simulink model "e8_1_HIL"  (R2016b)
settings: Solver=FixedStepDiscrete  StartTime=0.0  StopTime=10.0  RelTol=1e-3
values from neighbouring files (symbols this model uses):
  DEG2RAD = 0.0174533    [Init_control.m]
  Kd_PITCH_AgngleRate = 0.001    [Init_control.m]
  Kd_ROLL_AgngleRate = 0.001    [Init_control.m]
  Kd_YAW_AngleRate = 0.00    (= 0)    [Init_control.m]
  Ki_PITCH_AgngleRate = 0.02    [Init_control.m]
  Ki_ROLL_AgngleRate = 0.02    [Init_control.m]
  Ki_YAW_AngleRate = 0.01    [Init_control.m]
  Kp_PITCH_AgngleRate = 0.1    [Init_control.m]
  Kp_PITCH_ANGLE = 6.5    [Init_control.m]
  Kp_ROLL_AgngleRate = 0.1    [Init_control.m]
  Kp_ROLL_ANGLE = 6.5    [Init_control.m]
  Kp_YAW_AngleRate = 0.5    [Init_control.m]
  Kpxp = 1.0    (= 1)    [Init_control.m]
  Kpyp = 1.0    (= 1)    [Init_control.m]
  Kpzp = 4.0    (= 4)    [Init_control.m]
  Kvxd = 0.01    [Init_control.m]
  Kvxi = 0.1    [Init_control.m]
  Kvxp = 3.0    (= 3)    [Init_control.m]
  Kvyd = 0.01    [Init_control.m]
  Kvyi = 0.1    [Init_control.m]
  Kvyp = 3.0    (= 3)    [Init_control.m]
  Kvzd = 0.005    [Init_control.m]
  Kvzi = 0.01    [Init_control.m]
  Kvzp = 0.45    [Init_control.m]
  MAX_CONTROL_ANGLE_PITCH = 35    [Init_control.m]
  MAX_CONTROL_ANGLE_RATE_PITCH = 220    [Init_control.m]
  MAX_CONTROL_ANGLE_RATE_ROLL = 220    [Init_control.m]
  MAX_CONTROL_ANGLE_RATE_Y = 200    [Init_control.m]
  MAX_CONTROL_ANGLE_ROLL = 35    [Init_control.m]
  MAX_CONTROL_VELOCITY_XY = 5    [Init_control.m]
  MAX_CONTROL_VELOCITY_Z = 3    [Init_control.m]
  Saturation_I_ah = 3.43    [Init_control.m]
  Saturation_I_az = 5    [Init_control.m]
  Saturation_I_RP_Max = 0.3    [Init_control.m]
  Saturation_I_RP_Min = -0.3    [Init_control.m]
  Saturation_I_Y_Max = 0.2    [Init_control.m]
  Saturation_I_Y_Min = -0.2    [Init_control.m]
  THR_HOVER = 0.609    [Init_control.m]
undefined symbols (not defined in the file or in its folder): DiscIntNeverNeededParam, KiRollAttitude, RGBLED_COLOR_ENUM, RGBLED_MODE_ENUM
libraries: simulink x10, pixhawk_slib_sensors_actuators x4, pixhawk_slib_uORB_RW x2

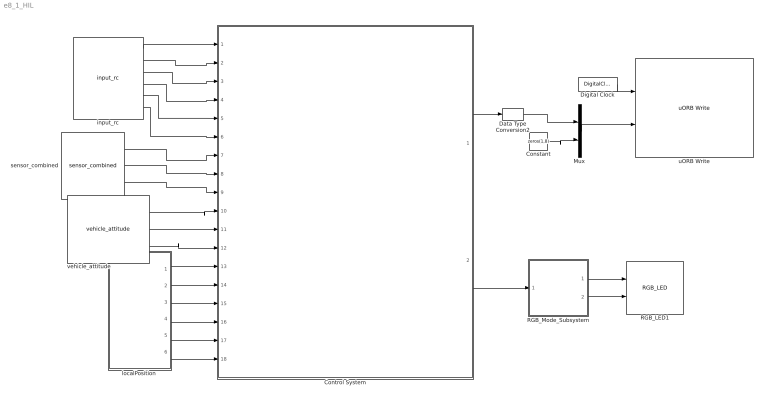
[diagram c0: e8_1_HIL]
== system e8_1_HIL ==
  Constant : Constant  Value=zeros(1,8)
  Control System : Subsystem
  Data Type Conversion2 : DataTypeConversion  OutDataTypeStr=double
  Digital Clock : DigitalClock  SampleTime=-1
  Mux : Mux  Inputs=2
  RGB_LED1 : pixhawk_slib_sensors_actuators/RGB_LED
  RGB_Mode_Subsystem : Subsystem
  input_rc : pixhawk_slib_sensors_actuators/input_rc  sampletime=0.004  channel1=on  channel2=on  channel3=on  channel4=on  channel5=on  channel6=on  channel7=off  channel8=off  ch_count=off  rssi=off  rc_failsafe=off  rc_lost=off  rc_inputsource=off
  "localPosition " : Subsystem
  sensor_combined : pixhawk_slib_sensors_actuators/sensor_combined  sampletime=0.004  show_mag=off  show_acc=off  show_gyro=on  show_baro=off  show_ts=off
  uORB Write : pixhawk_slib_uORB_RW/uORB Write  uORB_Topic_str='actuator_outputs'  BlockOutputCount=2  OutputBoolean_1=on  uORB_Param_Name1='timestamp'  uORB_Param_Name_DT1=double  VectorScalar_1=1  OutputBoolean_2=on  uORB_Param_Name2='output'  uORB_Param_Name_DT2=double  VectorScalar_2=16  OutputBoolean_3=off  uORB_Param_Name3='timestamp_time'  uORB_Param_Name_DT3=double  VectorScalar_3=1  OutputBoolean_4=off  uORB_Param_Name4='gyro_temp'  uORB_Param_Name_DT4=single  VectorScalar_4=3  OutputBoolean_5=off  uORB_Param_Name5='vel_ned_valid'  uORB_Param_Name_DT5=boolean  VectorScalar_5=1  Ts=-1
  vehicle_attitude : pixhawk_slib_sensors_actuators/vehicle_attitude  sampletime=0.004  show_r=on  show_p=on  show_y=on  show_q=off
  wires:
  sensor_combined/1 -> Control System/7(p)
  sensor_combined/3 -> Control System/9(r)
  vehicle_attitude/1 -> Control System/10(roll)
  vehicle_attitude/2 -> Control System/11(pitch)
  sensor_combined/2 -> Control System/8(q)
  RGB_Mode_Subsystem/1(RGB_MODE) -> RGB_LED1/1
  RGB_Mode_Subsystem/2(RGB_COLOR) -> RGB_LED1/2
  Control System/2(LED) -> RGB_Mode_Subsystem/1(LED)
  Digital Clock/1 -> uORB Write/1
  Mux/1 -> uORB Write/2
  Control System/1(PWM) -> Data Type Conversion2/1
  Constant/1 -> Mux/2
  Data Type Conversion2/1 -> Mux/1
  vehicle_attitude/3 -> Control System/12(yaw)
  "localPosition "/1(x) -> Control System/13(x)
  "localPosition "/2(y) -> Control System/14(y)
  "localPosition "/3(z) -> Control System/15(z)
  "localPosition "/4(vx) -> Control System/16(vx)
  "localPosition "/5(vy) -> Control System/17(vy)
  "localPosition "/6(vz) -> Control System/18(vz)
  input_rc/5 -> Control System/5(ch5)
  input_rc/4 -> Control System/4(ch4)
  input_rc/3 -> Control System/3(ch3)
  input_rc/2 -> Control System/2(ch2)
  input_rc/1 -> Control System/1(ch1)
  input_rc/6 -> Control System/6("ch6 ")

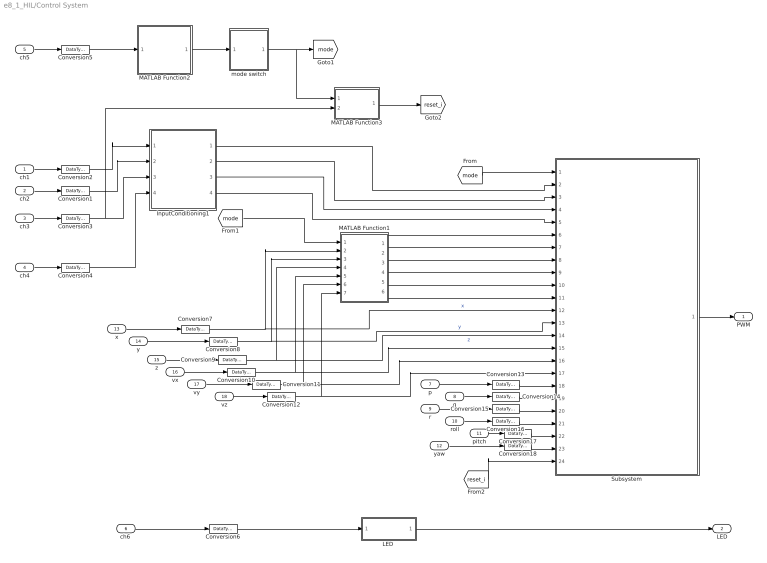
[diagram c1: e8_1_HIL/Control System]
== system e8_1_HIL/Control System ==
  ch1 : Inport  OutDataTypeStr=uint16  PortDimensions=1
  ch2 : Inport  Port=2  OutDataTypeStr=uint16  PortDimensions=1
  ch3 : Inport  Port=3  OutDataTypeStr=uint16  PortDimensions=1
  ch4 : Inport  Port=4  OutDataTypeStr=uint16  PortDimensions=1
  ch5 : Inport  Port=5  OutDataTypeStr=uint16  PortDimensions=1
  "ch6 " : Inport  Port=6  OutDataTypeStr=uint16  PortDimensions=1  Interpolate=off
  p : Inport  Port=7  PortDimensions=1
  q : Inport  Port=8  PortDimensions=1
  r : Inport  Port=9  PortDimensions=1
  roll : Inport  Port=10  PortDimensions=1
  pitch : Inport  Port=11  PortDimensions=1
  yaw : Inport  Port=12  PortDimensions=1
  x : Inport  Port=13
  y : Inport  Port=14
  z : Inport  Port=15
  vx : Inport  Port=16
  vy : Inport  Port=17
  vz : Inport  Port=18
  Conversion{1..18} (18 alike) : DataTypeConversion  OutDataTypeStr=double
  InputConditioning1 : Subsystem
  "LED " : Subsystem
  MATLAB Function1 : MATLAB Function  TreatAsAtomicUnit=on
  MATLAB Function2 : MATLAB Function  TreatAsAtomicUnit=on
  MATLAB Function3 : MATLAB Function  TreatAsAtomicUnit=on
  Subsystem : Subsystem
  mode switch : Stateflow chart  TreatAsAtomicUnit=on
  PWM : Outport
  LED : Outport  Port=2  PortDimensions=1
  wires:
  ch3/1 -> Conversion3/1
  "ch6 "/1 -> Conversion6/1
  ch4/1 -> Conversion4/1
  "LED "/1(Out1) -> LED/1
  Conversion6/1 -> "LED "/1(In1)
  Conversion4/1 -> InputConditioning1/4(yaw)
  ch1/1 -> Conversion2/1
  ch2/1 -> Conversion1/1
  y/1 -> Conversion8/1
  z/1 -> Conversion9/1
  roll/1 -> Conversion16/1
  pitch/1 -> Conversion17/1
  p/1 -> Conversion13/1
  q/1 -> Conversion14/1
  r/1 -> Conversion15/1
  Subsystem/1(PWM) -> PWM/1
  yaw/1 -> Conversion18/1
  vz/1 -> Conversion12/1
  vy/1 -> Conversion11/1
  vx/1 -> Conversion10/1
  MATLAB Function1/1(vxd) -> Subsystem/6(vx_d)
  MATLAB Function1/2(vyd) -> Subsystem/7(vy_d)
  MATLAB Function1/3(vzd) -> Subsystem/8(vz_d)
  MATLAB Function1/4(xd) -> Subsystem/9(x_d)
  MATLAB Function1/5(yd) -> Subsystem/10(y_d)
  x/1 -> Conversion7/1
  InputConditioning1/2(Roll) -> Subsystem/3(roll_d)
  InputConditioning1/3(Pitch) -> Subsystem/4(pitch_d)
  InputConditioning1/1(Thrust) -> Subsystem/2(thrust_d)
  InputConditioning1/4(Yaw) -> Subsystem/5(yaw_d)
  MATLAB Function2/1(control_mode) -> mode switch/1(mode)
  [mode] -> Subsystem/1(mode)
  ch5/1 -> Conversion5/1
  Conversion5/1 -> MATLAB Function2/1(ch5)
  MATLAB Function1/6(zd) -> Subsystem/11(z_d)
  [mode] -> MATLAB Function1/1(state)
  Conversion3/1 -> MATLAB Function3/2(ch3), InputConditioning1/3(thrust)
  mode switch/1(state) -> MATLAB Function3/1(mode), [mode]
  MATLAB Function3/1(reset_i) -> [reset_i]
  [reset_i] -> Subsystem/24(reset_i)
  Conversion10/1 -> Subsystem/15(vx), MATLAB Function1/5(vx)
  Conversion11/1 -> Subsystem/16(vy), MATLAB Function1/6(vy)
  Conversion12/1 -> Subsystem/17(vz), MATLAB Function1/7(vz)
  Conversion13/1 -> Subsystem/18(p)
  Conversion14/1 -> Subsystem/19(q)
  Conversion15/1 -> Subsystem/20(r)
  Conversion16/1 -> Subsystem/21(roll)
  Conversion17/1 -> Subsystem/22(pitch)
  Conversion18/1 -> Subsystem/23(psi)
  Conversion2/1 -> InputConditioning1/1(roll)
  Conversion1/1 -> InputConditioning1/2(pitch)
  Conversion8/1 -> Subsystem/13(y), MATLAB Function1/3(y)  "y"
  Conversion9/1 -> Subsystem/14(z), MATLAB Function1/4(z)  "z"
  Conversion7/1 -> Subsystem/12(x), MATLAB Function1/2(x)  "x"

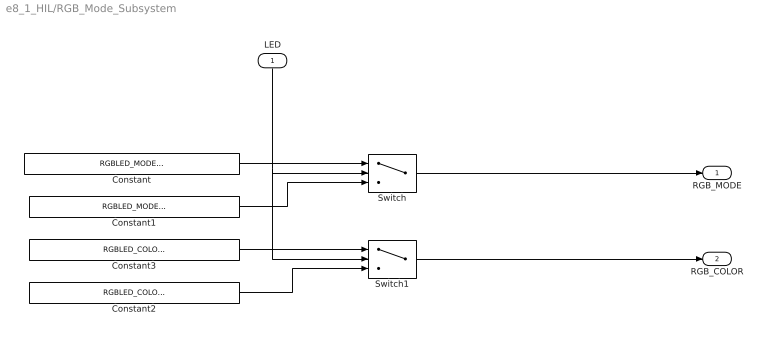
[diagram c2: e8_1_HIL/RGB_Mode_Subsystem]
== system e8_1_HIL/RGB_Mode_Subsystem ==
  LED : Inport
  Constant : Constant  Value=RGBLED_MODE_ENUM.MODE_BLINK_FAST  OutDataTypeStr=Enum: RGBLED_MODE_ENUM
  Constant1 : Constant  Value=RGBLED_MODE_ENUM.MODE_BREATHE  OutDataTypeStr=Enum: RGBLED_MODE_ENUM
  Constant2 : Constant  Value=RGBLED_COLOR_ENUM.COLOR_GREEN  OutDataTypeStr=Enum: RGBLED_COLOR_ENUM
  Constant3 : Constant  Value=RGBLED_COLOR_ENUM.COLOR_RED  OutDataTypeStr=Enum: RGBLED_COLOR_ENUM
  Switch : Switch  Criteria=u2 ~= 0  Threshold=1500  SampleTime=1/2
  Switch1 : Switch  Criteria=u2 ~= 0  Threshold=1500  SampleTime=1/2
  RGB_MODE : Outport
  RGB_COLOR : Outport  Port=2
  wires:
  LED/1 -> Switch1/2, Switch/2
  Constant/1 -> Switch/1
  Constant1/1 -> Switch/3
  Switch/1 -> RGB_MODE/1
  Constant3/1 -> Switch1/1
  Constant2/1 -> Switch1/3
  Switch1/1 -> RGB_COLOR/1

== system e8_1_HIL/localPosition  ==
  Bus Selector2 : BusSelector  OutputSignals=x,y,z,vx,vy,vz
  uORB Read / Function-Call Trigger1 : pixhawk_slib_uORB_RW/uORB Read // Function-Call Trigger  uORB_Topic_str='vehicle_local_position'  BusObjVar=Bus: vehicle_local_position_SL  uORB_Interval=4  AsyncOutput=off  Fcn_call_select=Generate Function Call Signal  TaskName='Task1'  Poll_timeout=100  Ts=-1
  x : Outport
  y : Outport  Port=2
  z : Outport  Port=3
  vx : Outport  Port=4
  vy : Outport  Port=5
  vz : Outport  Port=6
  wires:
  uORB Read / Function-Call Trigger1/1 -> Bus Selector2/1
  Bus Selector2/6 -> vz/1  "<vz>"
  Bus Selector2/5 -> vy/1  "<vy>"
  Bus Selector2/4 -> vx/1  "<vx>"
  Bus Selector2/1 -> x/1  "<x>"
  Bus Selector2/2 -> y/1  "<y>"
  Bus Selector2/3 -> z/1  "<z>"

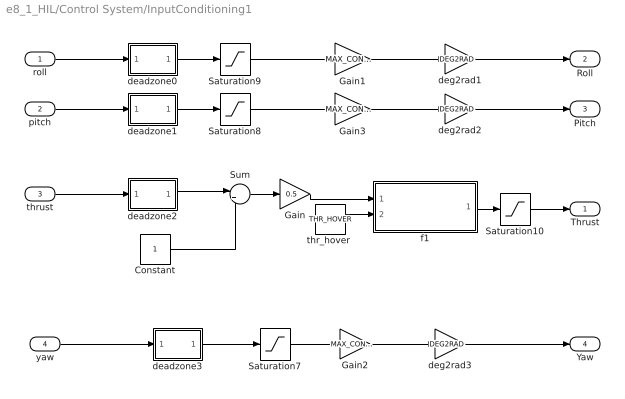
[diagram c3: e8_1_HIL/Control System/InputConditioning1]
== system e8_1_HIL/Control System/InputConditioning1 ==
  roll : Inport
  pitch : Inport  Port=2
  thrust : Inport  Port=3
  yaw : Inport  Port=4
  Constant : Constant
  Gain : Gain  Gain=0.5
  Gain1 : Gain  Gain=MAX_CONTROL_ANGLE_ROLL  OutDataTypeStr=Inherit: Inherit via back propagation
  Gain2 : Gain  Gain=MAX_CONTROL_ANGLE_RATE_Y
  Gain3 : Gain  Gain=MAX_CONTROL_ANGLE_PITCH  OutDataTypeStr=Inherit: Inherit via back propagation
  Saturation10 : Saturate  UpperLimit=1  LowerLimit=0
  Saturation7 : Saturate  UpperLimit=1  LowerLimit=-1
  Saturation8 : Saturate  UpperLimit=1  LowerLimit=-1
  Saturation9 : Saturate  UpperLimit=1  LowerLimit=-1
  Sum : Sum  Inputs=|++
  deadzone0 : MATLAB Function  TreatAsAtomicUnit=on
  deadzone1 : MATLAB Function  TreatAsAtomicUnit=on
  deadzone2 : MATLAB Function  TreatAsAtomicUnit=on
  deadzone3 : MATLAB Function  TreatAsAtomicUnit=on
  deg2rad1 : Gain  Gain=DEG2RAD
  deg2rad2 : Gain  Gain=DEG2RAD
  deg2rad3 : Gain  Gain=DEG2RAD
  f1 : MATLAB Function  TreatAsAtomicUnit=on
  "thr_hover " : Constant  Value=THR_HOVER
  Thrust : Outport
  Roll : Outport  Port=2
  Pitch : Outport  Port=3
  Yaw : Outport  Port=4
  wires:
  deadzone2/1(y) -> Sum/1
  thrust/1 -> deadzone2/1(u)
  deadzone1/1(y) -> Saturation8/1
  deadzone0/1(y) -> Saturation9/1
  roll/1 -> deadzone0/1(u)
  pitch/1 -> deadzone1/1(u)
  Saturation9/1 -> Gain1/1
  Saturation8/1 -> Gain3/1
  Gain3/1 -> deg2rad2/1
  Constant/1 -> Sum/2
  Sum/1 -> Gain/1
  Gain1/1 -> deg2rad1/1
  deg2rad1/1 -> Roll/1
  deg2rad2/1 -> Pitch/1
  Saturation7/1 -> Gain2/1
  deadzone3/1(y) -> Saturation7/1
  yaw/1 -> deadzone3/1(u)
  Gain2/1 -> deg2rad3/1
  f1/1(y) -> Saturation10/1
  "thr_hover "/1 -> f1/2(hover)
  Gain/1 -> f1/1(in)
  Saturation10/1 -> Thrust/1
  deg2rad3/1 -> Yaw/1

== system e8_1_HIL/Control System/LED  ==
  In1 : Inport
  Compare To Constant3 : simulink/Logic and Bit Operations/Compare To Constant  relop=>=  const=uint16(1500)  OutDataTypeStr=boolean
  Out1 : Outport
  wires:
  Compare To Constant3/1 -> Out1/1
  In1/1 -> Compare To Constant3/1

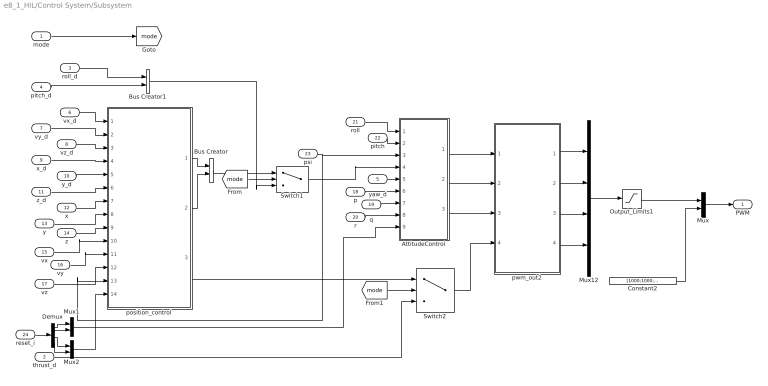
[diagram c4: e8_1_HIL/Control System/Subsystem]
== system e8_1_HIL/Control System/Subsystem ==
  mode : Inport
  thrust_d : Inport  Port=2
  roll_d : Inport  Port=3
  pitch_d : Inport  Port=4
  yaw_d : Inport  Port=5
  vx_d : Inport  Port=6
  vy_d : Inport  Port=7
  vz_d : Inport  Port=8
  x_d : Inport  Port=9
  y_d : Inport  Port=10
  z_d : Inport  Port=11
  x : Inport  Port=12
  y : Inport  Port=13
  z : Inport  Port=14
  vx : Inport  Port=15
  vy : Inport  Port=16
  vz : Inport  Port=17
  p : Inport  Port=18  PortDimensions=1
  q : Inport  Port=19  PortDimensions=1
  r : Inport  Port=20  PortDimensions=1
  roll : Inport  Port=21  PortDimensions=1
  pitch : Inport  Port=22  PortDimensions=1
  psi : Inport  Port=23  PortDimensions=1
  reset_i : Inport  Port=24
  AttitudeControl : Subsystem
  Bus Creator : BusCreator  Inputs=2
  Bus Creator1 : BusCreator  Inputs=2
  Constant2 : Constant  Value=[1000;1000;1000;1000]
  Demux : Demux
  Mux : Mux  Inputs=2
  Mux1 : Mux  Inputs=2
  Mux12 : Mux
  Mux2 : Mux  Inputs=2
  Output_Limits1 : Saturate  UpperLimit=2000  LowerLimit=1000
  Switch1 : Switch  Threshold=1
  Switch2 : Switch  Threshold=1
  position_control : Subsystem
  pwm_out2 : MATLAB Function  TreatAsAtomicUnit=on  SystemSampleTime=0.004
  PWM : Outport  PortDimensions=8
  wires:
  pwm_out2/4(M4) -> Mux12/4
  pwm_out2/3(M3) -> Mux12/3
  yaw_d/1 -> AttitudeControl/5(yaw)
  roll/1 -> AttitudeControl/1(phi)
  Mux/1 -> PWM/1
  q/1 -> AttitudeControl/7(q)
  AttitudeControl/1(Roll) -> pwm_out2/1(Roll)
  pwm_out2/2(M2) -> Mux12/2
  AttitudeControl/2(Pitch) -> pwm_out2/2(Pitch)
  pitch/1 -> AttitudeControl/2(theta)
  Mux12/1 -> Output_Limits1/1
  position_control/2(theta) -> Bus Creator/2
  pwm_out2/1(M1) -> Mux12/1
  AttitudeControl/3(Yaw) -> pwm_out2/3(Yaw)
  Output_Limits1/1 -> Mux/1
  position_control/1(phi) -> Bus Creator/1
  p/1 -> AttitudeControl/6(p)
  vx/1 -> position_control/10(vx)
  vz/1 -> position_control/12(vz)
  vy/1 -> position_control/11(vy)
  x_d/1 -> position_control/4(x_desired)
  y_d/1 -> position_control/5(y_desired)
  z_d/1 -> position_control/6(z_desired)
  mode/1 -> [mode]
  vz_d/1 -> position_control/3(vz_desired)
  x/1 -> position_control/7(x)
  vx_d/1 -> position_control/1(vx_desired)
  vy_d/1 -> position_control/2(vy_desired)
  y/1 -> position_control/8(y)
  z/1 -> position_control/9(z)
  Bus Creator/1 -> Switch1/1
  [mode] -> Switch1/2
  Switch1/1 -> AttitudeControl/4(roll_pitch)
  roll_d/1 -> Bus Creator1/1
  pitch_d/1 -> Bus Creator1/2
  Bus Creator1/1 -> Switch1/3
  [mode] -> Switch2/2
  position_control/3(thr) -> Switch2/1
  Switch2/1 -> pwm_out2/4(Thrust)
  thrust_d/1 -> Switch2/3
  r/1 -> AttitudeControl/8(r)
  psi/1 -> AttitudeControl/3(psi), position_control/13(psi)
  Constant2/1 -> Mux/2
  reset_i/1 -> Demux/1
  Mux2/1 -> position_control/14(reset_i)
  Mux1/1 -> AttitudeControl/9(reset_i)
  Demux/1 -> Mux1/1
  Demux/2 -> Mux1/2
  Demux/3 -> Mux2/1
  Demux/4 -> Mux2/2

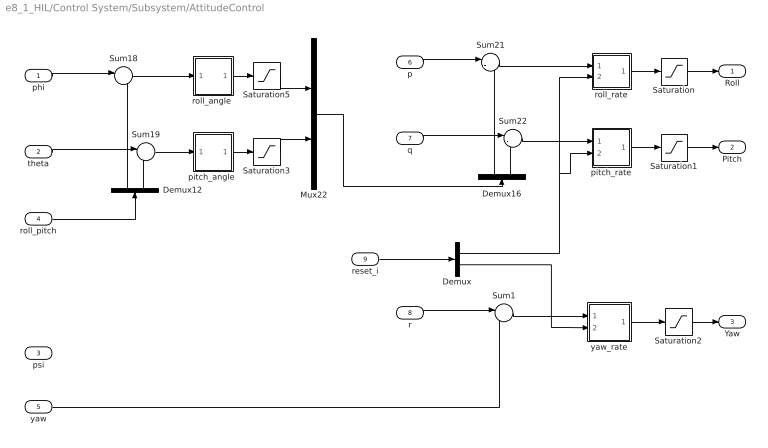
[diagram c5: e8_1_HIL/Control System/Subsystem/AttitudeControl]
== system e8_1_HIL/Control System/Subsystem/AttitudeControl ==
  phi : Inport
  theta : Inport  Port=2
  psi : Inport  Port=3
  roll_pitch : Inport  Port=4
  yaw : Inport  Port=5
  p : Inport  Port=6
  q : Inport  Port=7
  r : Inport  Port=8
  reset_i : Inport  Port=9
  Demux : Demux  Outputs=2
  Demux12 : Demux  Outputs=2
  Demux16 : Demux  Outputs=2
  Mux22 : Mux  Inputs=2
  Saturation : Saturate  UpperLimit=1  LowerLimit=-1
  Saturation1 : Saturate  UpperLimit=1  LowerLimit=-1
  Saturation2 : Saturate
  Saturation3 : Saturate  UpperLimit=MAX_CONTROL_ANGLE_RATE_PITCH  LowerLimit=-MAX_CONTROL_ANGLE_RATE_PITCH
  Saturation5 : Saturate  UpperLimit=MAX_CONTROL_ANGLE_RATE_ROLL  LowerLimit=-MAX_CONTROL_ANGLE_RATE_ROLL
  Sum1 : Sum  Inputs=|-+
  Sum18 : Sum  Inputs=|-+  OutMin=-90  OutMax=90
  Sum19 : Sum  Inputs=|-+  OutMin=-90  OutMax=90
  Sum21 : Sum  Inputs=|-+
  Sum22 : Sum  Inputs=|-+
  "pitch_angle " : Subsystem
  pitch_rate : Subsystem
  "roll_angle " : Subsystem
  roll_rate : Subsystem
  yaw_rate : Subsystem
  Roll : Outport
  Pitch : Outport  Port=2
  Yaw : Outport  Port=3
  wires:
  Sum19/1 -> "pitch_angle "/1(x)
  "pitch_angle "/1(y) -> Saturation3/1
  Demux12/1 -> Sum18/2
  Demux12/2 -> Sum19/2
  phi/1 -> Sum18/1
  theta/1 -> Sum19/1
  Sum18/1 -> "roll_angle "/1(x)
  Sum22/1 -> pitch_rate/1(x)
  p/1 -> Sum21/1
  q/1 -> Sum22/1
  Sum21/1 -> roll_rate/1(x)
  Demux16/1 -> Sum21/2
  pitch_rate/1(y) -> Saturation1/1
  roll_rate/1(y) -> Saturation/1
  yaw_rate/1(y) -> Saturation2/1
  roll_pitch/1 -> Demux12/1
  Saturation/1 -> Roll/1
  Saturation1/1 -> Pitch/1
  Saturation2/1 -> Yaw/1
  Demux16/2 -> Sum22/2
  Mux22/1 -> Demux16/1
  r/1 -> Sum1/1
  Sum1/1 -> yaw_rate/1(x)
  "roll_angle "/1(y) -> Saturation5/1
  Saturation5/1 -> Mux22/1
  Saturation3/1 -> Mux22/2
  yaw/1 -> Sum1/2
  Demux/1 -> roll_rate/2(reset_i), pitch_rate/2(reset_i)
  reset_i/1 -> Demux/1
  Demux/2 -> yaw_rate/2(reset_i)

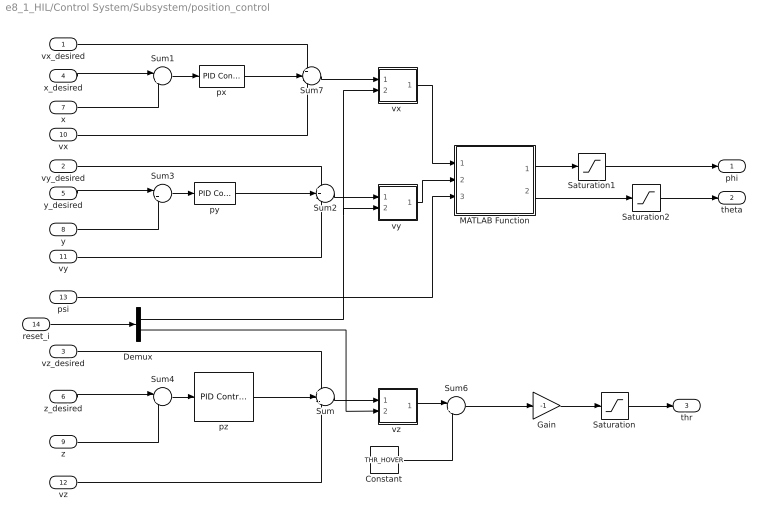
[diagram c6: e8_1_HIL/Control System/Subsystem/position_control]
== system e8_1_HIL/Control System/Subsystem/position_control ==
  vx_desired : Inport
  vy_desired : Inport  Port=2
  vz_desired : Inport  Port=3
  x_desired : Inport  Port=4
  y_desired : Inport  Port=5
  z_desired : Inport  Port=6
  x : Inport  Port=7
  y : Inport  Port=8
  z : Inport  Port=9
  vx : Inport  Port=10
  vy : Inport  Port=11
  vz : Inport  Port=12
  psi : Inport  Port=13
  reset_i : Inport  Port=14
  Constant : Constant  Value=THR_HOVER
  Demux : Demux  Outputs=2
  Gain : Gain  Gain=-1
  MATLAB Function : MATLAB Function  TreatAsAtomicUnit=on
  Saturation : Saturate  UpperLimit=0.9  LowerLimit=0
  Saturation1 : Saturate  UpperLimit=MAX_CONTROL_ANGLE_ROLL*DEG2RAD  LowerLimit=-MAX_CONTROL_ANGLE_ROLL*DEG2RAD
  Saturation2 : Saturate  UpperLimit=MAX_CONTROL_ANGLE_PITCH*DEG2RAD/2  LowerLimit=-MAX_CONTROL_ANGLE_PITCH*DEG2RAD/2
  Sum : Sum  Inputs=++-
  Sum{1,3..4,6} (4 alike) : Sum  Inputs=|+-
  Sum2 : Sum  Inputs=++-
  Sum7 : Sum  Inputs=++-
  px : simulink/Continuous/PID Controller  Controller=P  TimeDomain=Discrete-time  SampleTime=-1  IntegratorMethod=Forward Euler  FilterMethod=Forward Euler  Form=Parallel  UseFilter=on  ControllerParametersSource=internal  P=Kpxp  I=KiRollAttitude  D=0.01  N=100  InitialConditionSource=internal  InitialConditionForIntegrator=0  InitialConditionForFilter=0  ExternalReset=none  LimitOutput=on  UpperSaturationLimit=MAX_CONTROL_VELOCITY_XY  LowerSaturationLimit=-MAX_CONTROL_VELOCITY_XY  LinearizeAsGain=on  AntiWindupMode=back-calculation  Kb=1  TrackingMode=off  Kt=1  PParamMin=[]  PParamMax=[]  IParamMin=[]  IParamMax=[]  DParamMin=[]  DParamMax=[]  NParamMin=[]  NParamMax=[]  KbParamMin=[]  KbParamMax=[]  KtParamMin=[]  KtParamMax=[]  POutMin=[]  POutMax=[]  IOutMin=[]  IOutMax=[]  DOutMin=[]  DOutMax=[]  NOutMin=[]  NOutMax=[]  KbOutMin=[]  KbOutMax=[]  KtOutMin=[]  KtOutMax=[]  IntegratorOutMin=[]  IntegratorOutMax=[]  FilterOutMin=[]  FilterOutMax=[]  SumOutMin=[]  SumOutMax=[]  SumI1OutMin=[]  SumI1OutMax=[]  SumI2OutMin=[]  SumI2OutMax=[]  SumI3OutMin=[]  SumI3OutMax=[]  SumDOutMin=[]  SumDOutMax=[]  SaturationOutMin=[]  SaturationOutMax=[]  IntegratorContinuousStateAttributes=''  IntegratorStateMustResolveToSignalObject=off  IntegratorRTWStateStorageClass=Auto  FilterContinuousStateAttributes=''  FilterStateMustResolveToSignalObject=off  FilterRTWStateStorageClass=Auto  DifferentiatorICPrevScaledInput=0  DifferentiatorOutMin=[]  DifferentiatorOutMax=[]
  py : simulink/Continuous/PID Controller  Controller=P  TimeDomain=Discrete-time  SampleTime=-1  IntegratorMethod=Forward Euler  FilterMethod=Forward Euler  Form=Parallel  UseFilter=on  ControllerParametersSource=internal  P=Kpyp  I=KiRollAttitude  D=0.01  N=100  InitialConditionSource=internal  InitialConditionForIntegrator=0  InitialConditionForFilter=0  ExternalReset=none  LimitOutput=on  UpperSaturationLimit=MAX_CONTROL_VELOCITY_XY  LowerSaturationLimit=-MAX_CONTROL_VELOCITY_XY  LinearizeAsGain=on  AntiWindupMode=back-calculation  Kb=1  TrackingMode=off  Kt=1  PParamMin=[]  PParamMax=[]  IParamMin=[]  IParamMax=[]  DParamMin=[]  DParamMax=[]  NParamMin=[]  NParamMax=[]  KbParamMin=[]  KbParamMax=[]  KtParamMin=[]  KtParamMax=[]  POutMin=[]  POutMax=[]  IOutMin=[]  IOutMax=[]  DOutMin=[]  DOutMax=[]  NOutMin=[]  NOutMax=[]  KbOutMin=[]  KbOutMax=[]  KtOutMin=[]  KtOutMax=[]  IntegratorOutMin=[]  IntegratorOutMax=[]  FilterOutMin=[]  FilterOutMax=[]  SumOutMin=[]  SumOutMax=[]  SumI1OutMin=[]  SumI1OutMax=[]  SumI2OutMin=[]  SumI2OutMax=[]  SumI3OutMin=[]  SumI3OutMax=[]  SumDOutMin=[]  SumDOutMax=[]  SaturationOutMin=[]  SaturationOutMax=[]  IntegratorContinuousStateAttributes=''  IntegratorStateMustResolveToSignalObject=off  IntegratorRTWStateStorageClass=Auto  FilterContinuousStateAttributes=''  FilterStateMustResolveToSignalObject=off  FilterRTWStateStorageClass=Auto  DifferentiatorICPrevScaledInput=0  DifferentiatorOutMin=[]  DifferentiatorOutMax=[]
  pz : simulink/Continuous/PID Controller  Controller=P  TimeDomain=Discrete-time  SampleTime=-1  IntegratorMethod=Forward Euler  FilterMethod=Forward Euler  Form=Parallel  UseFilter=on  ControllerParametersSource=internal  P=Kpzp  I=KiRollAttitude  D=0.01  N=100  InitialConditionSource=internal  InitialConditionForIntegrator=0  InitialConditionForFilter=0  ExternalReset=none  LimitOutput=on  UpperSaturationLimit=MAX_CONTROL_VELOCITY_Z  LowerSaturationLimit=-MAX_CONTROL_VELOCITY_Z  LinearizeAsGain=on  AntiWindupMode=back-calculation  Kb=1  TrackingMode=off  Kt=1  PParamMin=[]  PParamMax=[]  IParamMin=[]  IParamMax=[]  DParamMin=[]  DParamMax=[]  NParamMin=[]  NParamMax=[]  KbParamMin=[]  KbParamMax=[]  KtParamMin=[]  KtParamMax=[]  POutMin=[]  POutMax=[]  IOutMin=[]  IOutMax=[]  DOutMin=[]  DOutMax=[]  NOutMin=[]  NOutMax=[]  KbOutMin=[]  KbOutMax=[]  KtOutMin=[]  KtOutMax=[]  IntegratorOutMin=[]  IntegratorOutMax=[]  FilterOutMin=[]  FilterOutMax=[]  SumOutMin=[]  SumOutMax=[]  SumI1OutMin=[]  SumI1OutMax=[]  SumI2OutMin=[]  SumI2OutMax=[]  SumI3OutMin=[]  SumI3OutMax=[]  SumDOutMin=[]  SumDOutMax=[]  SaturationOutMin=[]  SaturationOutMax=[]  IntegratorContinuousStateAttributes=''  IntegratorStateMustResolveToSignalObject=off  IntegratorRTWStateStorageClass=Auto  FilterContinuousStateAttributes=''  FilterStateMustResolveToSignalObject=off  FilterRTWStateStorageClass=Auto  DifferentiatorICPrevScaledInput=0  DifferentiatorOutMin=[]  DifferentiatorOutMax=[]
  "vx " : Subsystem
  "vy " : Subsystem
  "vz " : Subsystem
  phi : Outport
  theta : Outport  Port=2
  thr : Outport  Port=3
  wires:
  Saturation/1 -> thr/1
  Gain/1 -> Saturation/1
  Sum6/1 -> Gain/1
  "vz "/1(y) -> Sum6/1
  Sum4/1 -> pz/1
  z/1 -> Sum4/2
  Constant/1 -> Sum6/2
  Sum/1 -> "vz "/1(x)
  vz/1 -> Sum/3
  vx/1 -> Sum7/3
  x/1 -> Sum1/2
  y/1 -> Sum3/2
  Sum3/1 -> py/1
  y_desired/1 -> Sum3/1
  vy/1 -> Sum2/3
  Sum2/1 -> "vy "/1(x)
  Sum7/1 -> "vx "/1(x)
  Sum1/1 -> px/1
  vy_desired/1 -> Sum2/1
  py/1 -> Sum2/2
  pz/1 -> Sum/2
  z_desired/1 -> Sum4/1
  vz_desired/1 -> Sum/1
  "vx "/1(y) -> MATLAB Function/1(eax)
  px/1 -> Sum7/2
  Saturation1/1 -> phi/1
  Saturation2/1 -> theta/1
  x_desired/1 -> Sum1/1
  vx_desired/1 -> Sum7/1
  "vy "/1(y) -> MATLAB Function/2(eay)
  psi/1 -> MATLAB Function/3(psi)
  MATLAB Function/1(phi) -> Saturation1/1
  MATLAB Function/2(theta) -> Saturation2/1
  reset_i/1 -> Demux/1
  Demux/1 -> "vy "/2(reset_i), "vx "/2(reset_i)
  Demux/2 -> "vz "/2(reset_i)

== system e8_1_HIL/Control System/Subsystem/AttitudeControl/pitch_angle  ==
  x : Inport
  Gain : Gain  Gain=Kp_PITCH_ANGLE
  y : Outport  InitialOutput=0
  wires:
  x/1 -> Gain/1
  Gain/1 -> y/1

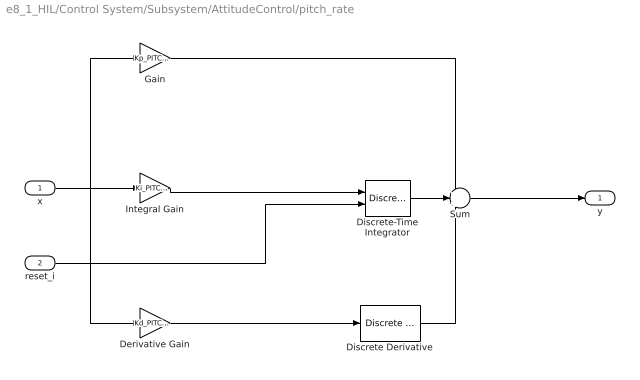
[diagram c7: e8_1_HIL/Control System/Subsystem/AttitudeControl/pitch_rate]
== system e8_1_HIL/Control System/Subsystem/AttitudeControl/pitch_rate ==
  x : Inport
  reset_i : Inport  Port=2
  Derivative Gain : Gain  DisableCoverage=on  Gain=Kd_PITCH_AgngleRate  ParamMin=-100  ParamMax=100  OutMin=-100  OutMax=100
  Discrete Derivative : simulink/Discrete/Discrete Derivative  gainval=1.0  ICPrevScaledInput=0.0  OutMin=[]  OutMax=[]  OutDataType=fixdt(1, 16)  OutScaling=2^-10  DoSatur=off
  Discrete-Time Integrator : DiscreteIntegrator  ExternalReset=level  InitialConditionSetting=State (most efficient)  SampleTime=-1  LimitOutput=on  UpperSaturationLimit=Saturation_I_RP_Max  LowerSaturationLimit=Saturation_I_RP_Min  ICPrevOutput=DiscIntNeverNeededParam  ICPrevScaledInput=DiscIntNeverNeededParam
  Gain : Gain  Gain=Kp_PITCH_AgngleRate
  Integral Gain : Gain  DisableCoverage=on  Gain=Ki_PITCH_AgngleRate
  Sum : Sum  Inputs=+++
  y : Outport  InitialOutput=0
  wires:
  Discrete-Time Integrator/1 -> Sum/2
  Discrete Derivative/1 -> Sum/3
  Sum/1 -> y/1
  Gain/1 -> Sum/1
  Derivative Gain/1 -> Discrete Derivative/1
  Integral Gain/1 -> Discrete-Time Integrator/1
  x/1 -> Derivative Gain/1, Integral Gain/1, Gain/1
  reset_i/1 -> Discrete-Time Integrator/2

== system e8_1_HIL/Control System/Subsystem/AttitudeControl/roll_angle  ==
  x : Inport
  Gain : Gain  Gain=Kp_ROLL_ANGLE
  y : Outport  InitialOutput=0
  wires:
  Gain/1 -> y/1
  x/1 -> Gain/1

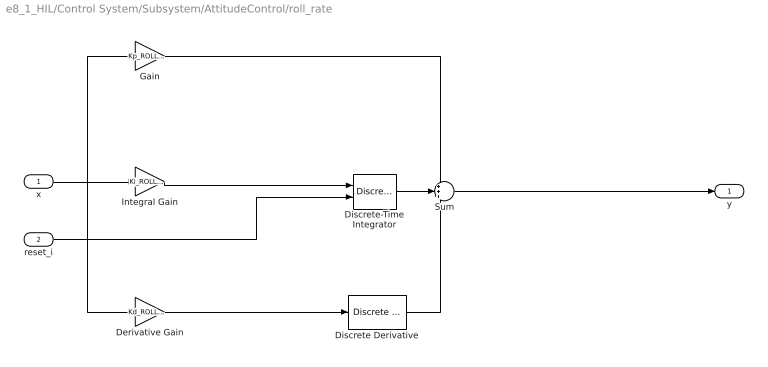
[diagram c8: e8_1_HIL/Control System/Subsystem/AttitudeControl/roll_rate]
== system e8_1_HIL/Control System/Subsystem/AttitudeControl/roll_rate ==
  x : Inport
  reset_i : Inport  Port=2
  Derivative Gain : Gain  DisableCoverage=on  Gain=Kd_ROLL_AgngleRate  ParamMin=-100  ParamMax=100  OutMin=-100  OutMax=100
  Discrete Derivative : simulink/Discrete/Discrete Derivative  gainval=1.0  ICPrevScaledInput=0.0  OutMin=[]  OutMax=[]  OutDataType=fixdt(1, 16)  OutScaling=2^-10  DoSatur=off
  Discrete-Time Integrator : DiscreteIntegrator  ExternalReset=level  InitialConditionSetting=State (most efficient)  SampleTime=-1  LimitOutput=on  UpperSaturationLimit=Saturation_I_RP_Max  LowerSaturationLimit=Saturation_I_RP_Min  ICPrevOutput=DiscIntNeverNeededParam  ICPrevScaledInput=DiscIntNeverNeededParam
  Gain : Gain  Gain=Kp_ROLL_AgngleRate
  Integral Gain : Gain  DisableCoverage=on  Gain=Ki_ROLL_AgngleRate
  Sum : Sum  Inputs=+++
  y : Outport  InitialOutput=0
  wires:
  x/1 -> Gain/1, Integral Gain/1, Derivative Gain/1
  Integral Gain/1 -> Discrete-Time Integrator/1
  Derivative Gain/1 -> Discrete Derivative/1
  Gain/1 -> Sum/1
  Sum/1 -> y/1
  Discrete Derivative/1 -> Sum/3
  Discrete-Time Integrator/1 -> Sum/2
  reset_i/1 -> Discrete-Time Integrator/2

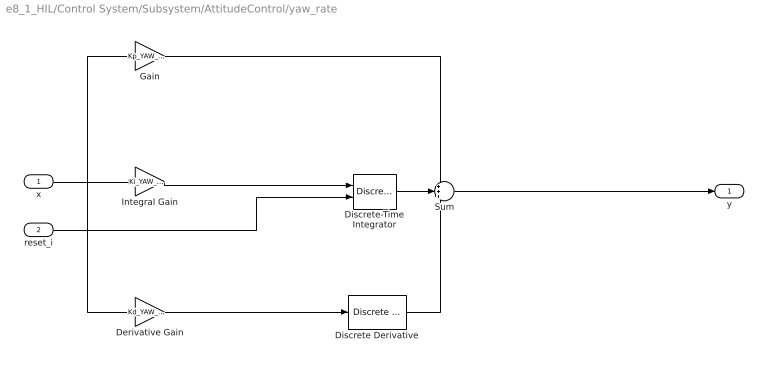
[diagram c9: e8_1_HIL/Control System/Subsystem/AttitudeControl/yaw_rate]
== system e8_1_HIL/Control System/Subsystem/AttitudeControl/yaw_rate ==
  x : Inport
  reset_i : Inport  Port=2
  Derivative Gain : Gain  DisableCoverage=on  Gain=Kd_YAW_AngleRate  ParamMin=-100  ParamMax=100  OutMin=-100  OutMax=100
  Discrete Derivative : simulink/Discrete/Discrete Derivative  gainval=1.0  ICPrevScaledInput=0.0  OutMin=[]  OutMax=[]  OutDataType=fixdt(1, 16)  OutScaling=2^-10  DoSatur=off
  Discrete-Time Integrator : DiscreteIntegrator  ExternalReset=level  InitialConditionSetting=State (most efficient)  SampleTime=-1  LimitOutput=on  UpperSaturationLimit=Saturation_I_Y_Max  LowerSaturationLimit=Saturation_I_Y_Min  ICPrevOutput=DiscIntNeverNeededParam  ICPrevScaledInput=DiscIntNeverNeededParam
  Gain : Gain  Gain=Kp_YAW_AngleRate
  Integral Gain : Gain  DisableCoverage=on  Gain=Ki_YAW_AngleRate
  Sum : Sum  Inputs=+++
  y : Outport  InitialOutput=0
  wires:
  x/1 -> Gain/1, Integral Gain/1, Derivative Gain/1
  Integral Gain/1 -> Discrete-Time Integrator/1
  Derivative Gain/1 -> Discrete Derivative/1
  Gain/1 -> Sum/1
  Sum/1 -> y/1
  Discrete Derivative/1 -> Sum/3
  Discrete-Time Integrator/1 -> Sum/2
  reset_i/1 -> Discrete-Time Integrator/2

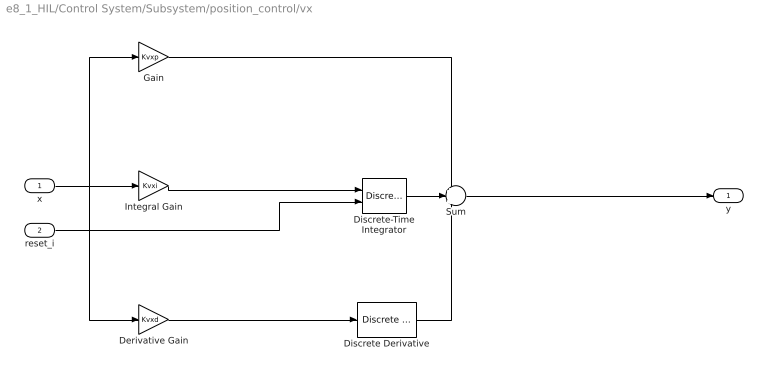
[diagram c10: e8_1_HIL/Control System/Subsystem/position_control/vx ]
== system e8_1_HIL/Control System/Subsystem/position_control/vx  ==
  x : Inport
  reset_i : Inport  Port=2
  Derivative Gain : Gain  DisableCoverage=on  Gain=Kvxd
  Discrete Derivative : simulink/Discrete/Discrete Derivative  gainval=1.0  ICPrevScaledInput=0.0  OutMin=[]  OutMax=[]  OutDataType=fixdt(1, 16)  OutScaling=2^-10  DoSatur=off
  Discrete-Time Integrator : DiscreteIntegrator  ExternalReset=level  InitialConditionSetting=State (most efficient)  SampleTime=-1  LimitOutput=on  UpperSaturationLimit=Saturation_I_ah  LowerSaturationLimit=-Saturation_I_ah  ICPrevOutput=DiscIntNeverNeededParam  ICPrevScaledInput=DiscIntNeverNeededParam
  Gain : Gain  Gain=Kvxp
  Integral Gain : Gain  DisableCoverage=on  Gain=Kvxi
  Sum : Sum  Inputs=+++
  y : Outport  InitialOutput=0
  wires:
  x/1 -> Gain/1, Integral Gain/1, Derivative Gain/1
  Integral Gain/1 -> Discrete-Time Integrator/1
  Derivative Gain/1 -> Discrete Derivative/1
  Gain/1 -> Sum/1
  Sum/1 -> y/1
  Discrete Derivative/1 -> Sum/3
  Discrete-Time Integrator/1 -> Sum/2
  reset_i/1 -> Discrete-Time Integrator/2

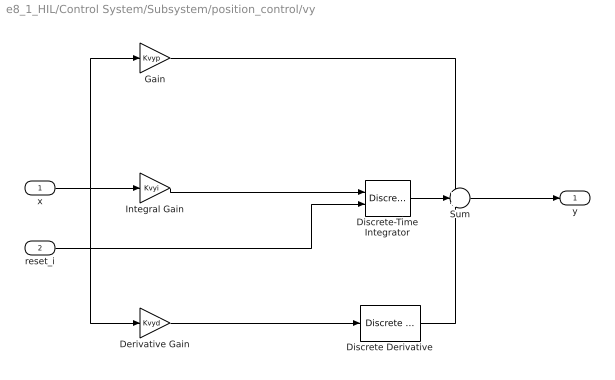
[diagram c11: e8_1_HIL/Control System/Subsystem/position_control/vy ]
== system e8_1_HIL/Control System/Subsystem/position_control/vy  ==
  x : Inport
  reset_i : Inport  Port=2
  Derivative Gain : Gain  DisableCoverage=on  Gain=Kvyd
  Discrete Derivative : simulink/Discrete/Discrete Derivative  gainval=1.0  ICPrevScaledInput=0.0  OutMin=[]  OutMax=[]  OutDataType=fixdt(1, 16)  OutScaling=2^-10  DoSatur=off
  Discrete-Time Integrator : DiscreteIntegrator  ExternalReset=level  InitialConditionSetting=State (most efficient)  SampleTime=-1  LimitOutput=on  UpperSaturationLimit=Saturation_I_ah  LowerSaturationLimit=-Saturation_I_ah  ICPrevOutput=DiscIntNeverNeededParam  ICPrevScaledInput=DiscIntNeverNeededParam
  Gain : Gain  Gain=Kvyp
  Integral Gain : Gain  DisableCoverage=on  Gain=Kvyi
  Sum : Sum  Inputs=+++
  y : Outport  InitialOutput=0
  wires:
  x/1 -> Gain/1, Integral Gain/1, Derivative Gain/1
  Integral Gain/1 -> Discrete-Time Integrator/1
  Derivative Gain/1 -> Discrete Derivative/1
  Gain/1 -> Sum/1
  Sum/1 -> y/1
  Discrete Derivative/1 -> Sum/3
  Discrete-Time Integrator/1 -> Sum/2
  reset_i/1 -> Discrete-Time Integrator/2

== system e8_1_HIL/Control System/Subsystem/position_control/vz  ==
  x : Inport
  reset_i : Inport  Port=2
  Derivative Gain : Gain  DisableCoverage=on  Gain=Kvzd
  Discrete Derivative : simulink/Discrete/Discrete Derivative  gainval=1.0  ICPrevScaledInput=0.0  OutMin=[]  OutMax=[]  OutDataType=fixdt(1, 16)  OutScaling=2^-10  DoSatur=off
  Discrete-Time Integrator : DiscreteIntegrator  ExternalReset=level  InitialConditionSetting=State (most efficient)  SampleTime=-1  LimitOutput=on  UpperSaturationLimit=Saturation_I_az  LowerSaturationLimit=-Saturation_I_az  ICPrevOutput=DiscIntNeverNeededParam  ICPrevScaledInput=DiscIntNeverNeededParam
  Gain : Gain  Gain=Kvzp
  Integral Gain : Gain  DisableCoverage=on  Gain=Kvzi
  Sum : Sum  Inputs=+++
  y : Outport  InitialOutput=0
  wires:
  Discrete-Time Integrator/1 -> Sum/2
  Discrete Derivative/1 -> Sum/3
  Sum/1 -> y/1
  Gain/1 -> Sum/1
  Derivative Gain/1 -> Discrete Derivative/1
  Integral Gain/1 -> Discrete-Time Integrator/1
  x/1 -> Derivative Gain/1, Integral Gain/1, Gain/1
  reset_i/1 -> Discrete-Time Integrator/2

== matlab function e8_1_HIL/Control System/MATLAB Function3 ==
function reset_i= fcn(mode,ch3)
if ch3<1250
    reset_i=[1 1 1 1];
elseif mode==0
    reset_i=[0 0 1 1];
elseif mode==1
    reset_i=[0 0 0 0];
else
    reset_i=[0 0 0 0];
end

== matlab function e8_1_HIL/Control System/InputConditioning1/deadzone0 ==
function y = fcn(u)
%将遥控输入的范围控制在1100~1900，同时设置一个死区，死区大小为±deadZone
RCMin = 1100;
RCMax = 1900;
RCMid = (RCMin+RCMax)/2;
deadZoneRate = 0.05;
deadZone = deadZoneRate*(RCMax-RCMin);
k=1/(RCMax-RCMid-deadZone);
%限幅
if(u < RCMin)
    u = RCMin;
elseif(u > RCMax)
    u = RCMax;
end
%死区
 if(u > RCMid+deadZone)
    y = (u-RCMid-deadZone)*k;
 elseif(u < RCMid-deadZone)
     y = (u-RCMid+deadZone)*k;
 else
     y = 0;
 end

 end

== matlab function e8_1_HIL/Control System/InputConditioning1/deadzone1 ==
function y = fcn(u)
%将遥控输入的范围控制在1100~1900，同时设置一个死区，死区大小为±deadZone
RCMin = 1100;
RCMax = 1900;
RCMid = (RCMin+RCMax)/2;
deadZoneRate = 0.05;
deadZone = deadZoneRate*(RCMax-RCMin);
k=1/(RCMax-RCMid-deadZone);
%限幅
if(u < RCMin)
    u = RCMin;
elseif(u > RCMax)
    u = RCMax;
end
%死区
 if(u > RCMid+deadZone)
    y = (u-RCMid-deadZone)*k;
 elseif(u < RCMid-deadZone)
     y = (u-RCMid+deadZone)*k;
 else
     y = 0;
 end

 end

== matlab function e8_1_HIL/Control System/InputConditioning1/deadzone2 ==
function y = fcn(u)
%将遥控输入的范围控制在1100~1900，同时设置一个死区，死区大小为±deadZone
RCMin = 1100;
RCMax = 1900;
RCMid = (RCMin+RCMax)/2;
deadZoneRate = 0.05;
deadZone = deadZoneRate*(RCMax-RCMin);
k=1/(RCMax-RCMid-deadZone);
%限幅
if(u < RCMin)
    u = RCMin;
elseif(u > RCMax)
    u = RCMax;
end
%死区
 if(u > RCMid+deadZone)
    y = (u-RCMid-deadZone)*k;
 elseif(u < RCMid-deadZone)
     y = (u-RCMid+deadZone)*k;
 else
     y = 0;
 end

 end

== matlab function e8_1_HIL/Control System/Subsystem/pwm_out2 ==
function [M1, M2, M3, M4] = motor_mixer(Roll, Pitch, Yaw, Thrust)

idle_PWM = 1000;

% Quad XROLL （根据QP里面的叉字形结构的文字）
% M1 = ((Pitch+ Yaw)+Thrust-Roll) * 1000 + idle_PWM;
 %M2 = ((Pitch - Yaw)+Thrust+Roll) * 1000 + idle_PWM;
 %M3 = ((Roll +Yaw) + Thrust-Pitch) * 1000 + idle_PWM;
 %M4 = ((-Roll - Pitch-Yaw) + Thrust) * 1000 + idle_PWM;
% M5 = 1000;
% M6 = 1000;
% M7 = 1000;
% M8 = 1000;
%qp上实际的输出
M1 = (Thrust+Pitch-Roll+Yaw)*1000  + idle_PWM;
M2 = (Thrust-Pitch +Roll+Yaw)*1000 + idle_PWM;
M3 = (Thrust+Roll+Pitch-Yaw)*1000  + idle_PWM;
M4 = (Thrust-Roll- Pitch -Yaw)*1000 + idle_PWM;
% Quad +
 %M1 = ((Pitch - Yaw) * Thrust / 2 + Thrust) * 1000 + idle_PWM;
 %M2 = ((-Roll + Yaw) * Thrust / 2 + Thrust) * 1000 + idle_PWM;
% M3 = ((-Pitch - Yaw) * Thrust / 2 + Thrust) * 1000 + idle_PWM;
 %M4 = ((Roll + Yaw) * Thrust / 2 + Thrust) * 1000 + idle_PWM;
% M5 = 1000;
% M6 = 1000;
% M7 = 1000;
% M8 = 1000;

% Hex X
% M1 = ((Pitch + Roll / 2 - Yaw) * Thrust / 2 + Thrust) * 1000 + idle_PWM;
% M2 = ((Pitch - Roll / 2 + Yaw) * Thrust / 2 + Thrust) * 1000 + idle_PWM;
% M3 = ((-Roll - Yaw) * Thrust / 2 + Thrust) * 1000 + idle_PWM;
% M4 = ((-Pitch - Roll / 2 + Yaw) * Thrust / 2 + Thrust) * 1000 + idle_PWM;
% M5 = ((-Pitch + Roll / 2 - Yaw) * Thrust / 2 + Thrust) * 1000 + idle_PWM;
% M6 = ((Roll + Yaw) * Thrust / 2 + Thrust) * 1000 + idle_PWM;
% M7 = 1000;
% M8 = 1000;

% Hex X (From Adam)
%M1 = uint16(single(((-Roll - Yaw) * Thrust / 3 + Thrust) * single(1000))) + idle_PWM;
%M2 = uint16(single(((Roll + Yaw) * Thrust / 3 + Thrust) * single(1000))) + idle_PWM;
%M3 = uint16(single(((Pitch + (Roll / 2) - Yaw) * Thrust / 3 + Thrust) * single(1000))) + idle_PWM;
%M4 = uint16(single(((-Pitch - (Roll / 2) + Yaw) * Thrust / 3 + Thrust) * single(1000))) + idle_PWM;
%M5 = uint16(single(((Pitch - (Roll / 2) + Yaw) * Thrust / 3 + Thrust) * single(1000))) + idle_PWM;
%M6 = uint16(single(((-Pitch + (Roll / 2) - Yaw) * Thrust / 3 + Thrust) * single(1000))) + idle_PWM;

% Hex X (Version 2)
% Roll/Yaw
% M1 = ((-Roll - Yaw) * Thrust / 2 + Thrust) * 1000 + idle_PWM;
% M2 = ((Roll + Yaw) * Thrust / 2 + Thrust) * 1000 + idle_PWM;
% % + Pitch/Roll
% M6 = ((Pitch + Roll / 2 - Yaw) * Thrust / 2 + Thrust) * 1000 + idle_PWM;
% M4 = ((Pitch - Roll / 2 + Yaw) * Thrust / 2 + Thrust) * 1000 + idle_PWM;
% % - Pitch/Roll
% M5 = ((-Pitch - Roll / 2 + Yaw) * Thrust / 2 + Thrust) * 1000 + idle_PWM;
% M3 = ((-Pitch + Roll / 2 - Yaw) * Thrust / 2 + Thrust) * 1000 + idle_PWM;

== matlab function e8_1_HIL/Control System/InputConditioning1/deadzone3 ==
function y = fcn(u)
%将遥控输入的范围控制在1100~1900，同时设置一个死区，死区大小为±deadZone
RCMin = 1100;
RCMax = 1900;
RCMid = (RCMin+RCMax)/2;
deadZoneRate = 0.05;
deadZone = deadZoneRate*(RCMax-RCMin);
k=1/(RCMax-RCMid-deadZone);
%限幅
if(u < RCMin)
    u = RCMin;
elseif(u > RCMax)
    u = RCMax;
end
%死区
 if(u > RCMid+deadZone)
    y = (u-RCMid-deadZone)*k;
 elseif(u < RCMid-deadZone)
     y = (u-RCMid+deadZone)*k;
 else
     y = 0;
 end

 end

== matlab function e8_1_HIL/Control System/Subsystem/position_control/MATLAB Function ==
function [phi,theta] = fcn(eax,eay,psi)
g=9.8;
phi = (-sin(psi)*eax + cos(psi)*eay)/g;
theta = (-cos(psi)*eax-sin(psi)*eay)/g;

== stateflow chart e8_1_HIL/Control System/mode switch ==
  state return1
    entry:state=1
  state land
    entry:state=2
  state manual
    entry:state=0
  manual -> return1 : [mode==1]
  return1 -> manual : [mode==0]
  land -> manual : [(mode==0)]
  manual -> land : [mode==2]
  (default) -> manual
  data: state output; mode input

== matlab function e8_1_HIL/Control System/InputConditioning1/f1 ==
function y = thr_curve(in,hover)
%输入油门归一化后为0~1，中点为0.5
%经过这个函数，油门在中间位置时，输出为悬停油门 hover
if in < 0.5
	y=2 * in * hover;
else
	y=hover + 2 * (in - 0.5) * (1.0 - hover);
end

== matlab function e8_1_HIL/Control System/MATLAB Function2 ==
function control_mode = fcn(ch5)
%0:手动飞行
%1：返航
%2：着陆
if ch5<1400
    control_mode=0;
elseif ch5<1600
    control_mode=1;
else
    control_mode=2;
end

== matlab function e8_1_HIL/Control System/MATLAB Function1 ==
function [vxd,vyd,vzd,xd,yd,zd] = fcn(state,x,y,z,vx,vy,vz)
persistent hold_x_flag;
if isempty(hold_x_flag)
    hold_x_flag=0;
end
persistent hold_y_flag;
if isempty(hold_y_flag)
    hold_y_flag=0;
end
persistent hold_z_flag;
if isempty(hold_z_flag)
    hold_z_flag=0;
end
persistent x1;
if isempty(x1)
    x1=0;
end
persistent y1;
if isempty(y1)
    y1=0;
end

persistent z1;
if isempty(z1)
    z1=0;
end

heightSafe=50;
if state==1 %返航，高度低于指定阈值，先上升到指定值
    vxd=0;%将水平速度降为0
    vyd=0;
    if abs(z)<heightSafe
        z1=-heightSafe;vzd=0;%期望高度设为50
        hold_z_flag = 0;
    else
        vzd = 0;
        if abs(vz)< 6 &&(hold_z_flag<0.5)
            z1 = z; 
            hold_z_flag=1;
        end
        if ~(abs(vz)<6)
           z1=z;
           hold_z_flag = 0;
        end
    end
    
    if abs(vx) < 8 && (hold_x_flag < 0.5)
       x1 = 0; 
       hold_x_flag = 1;
   end
   if ~(abs(vx) < 8)
       x1 = x; 
       hold_x_flag = 0;
   end
   if abs(vy)< 8 && (hold_y_flag < 0.5)
       y1 = 0;
       hold_y_flag = 1;
   end
   if ~(abs(vy) < 8)
       y1 = y;
       hold_y_flag = 0;
   end
elseif state==2%着陆
    vxd = 0; vyd = 0;
   z1 = 0;vzd = 0;%期望高度为0，进行着陆
   hold_z_flag = 0;
   %解决漂移问题
   if abs(vx) < 8 && (hold_x_flag < 0.5)
       x1 = x; 
       hold_x_flag = 1;
   end
   if ~(abs(vx) < 8)
       x1 = x; 
       hold_x_flag = 0;
   end
   if abs(vy) < 8 && (hold_y_flag < 0.5)
       y1 = y;
       hold_y_flag = 1;
   end
   if ~(abs(vy)<8)
       y1=y;
       hold_y_flag=0;
   end
   
else%手动
   x1 = x; vxd = 0;
   y1 = y; vyd = 0;
   z1 = z; vzd = 0;
   
   hold_x_flag = 0;
   hold_y_flag = 0;
   hold_z_flag = 0;
end

 xd=x1;
 yd=y1;
 zd=z1;
